VERSION 5.8 ;
BUSBITCHARS "[]" ;
DIVIDERCHAR "/" ;

UNITS
  DATABASE MICRONS 2000 ;
END UNITS

PROPERTYDEFINITIONS
  LAYER LEF58_TYPE STRING ;
  LAYER LEF58_BACKSIDE STRING ;
  MACRO LEF58_BACKSIDE_BRIDGE STRING ;
END PROPERTYDEFINITIONS

# Backside power-routing layer.
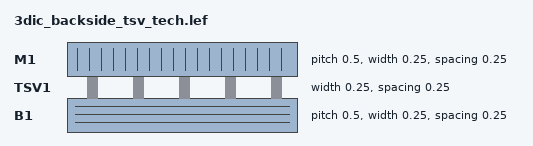
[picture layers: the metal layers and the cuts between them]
LAYER B1
  TYPE ROUTING ;
  DIRECTION HORIZONTAL ;
  WIDTH 0.250 ;
  PITCH 0.500 ;
  SPACING 0.250 ;
  RESISTANCE RPERSQ 0.020 ;
  PROPERTY LEF58_BACKSIDE "BACKSIDE ;" ;
END B1

# TSV technology layer. The test's electrical front/back connection is the
# TSV_BRIDGE macro in 3dic_backside_tsv_cells.lef.
LAYER TSV1
  TYPE CUT ;
  WIDTH 0.250 ;
  SPACING 0.250 ;
  RESISTANCE 0.001 ;
  PROPERTY LEF58_TYPE "TYPE TSV ;" ;
END TSV1

# Frontside power-routing layer.
LAYER M1
  TYPE ROUTING ;
  DIRECTION VERTICAL ;
  WIDTH 0.250 ;
  PITCH 0.500 ;
  SPACING 0.250 ;
  RESISTANCE RPERSQ 0.050 ;
END M1

END LIBRARY

